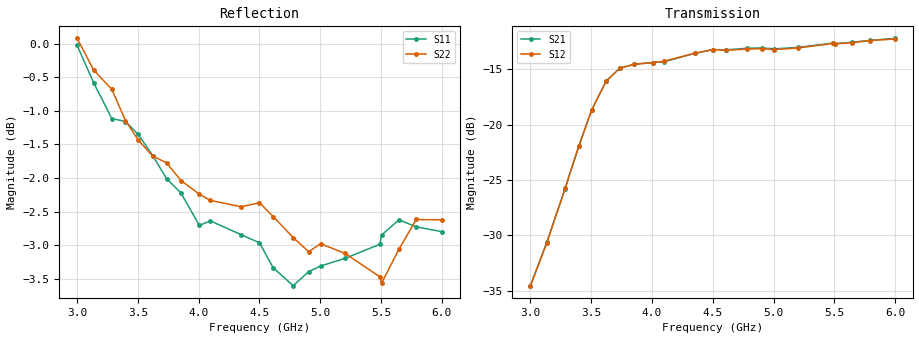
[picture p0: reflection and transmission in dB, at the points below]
!  26/11/2025  13:56:33
! Ref Plane: 0.000 mm
# MHZ S MA R  50
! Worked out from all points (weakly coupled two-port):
!   401 points, 3 GHz to 6 GHz, reference 50 ohm
!   highest |S21| = -12.19 dB at 6 GHz (marker M1); lowest = -34.5 dB at 3 GHz (marker M2)
!   lowest |S11| = -3.6 dB at 4.777 GHz (marker M3), VSWR 4.89, Z = 119 - j117 ohm
!   |S11| at or under -10 dB: nowhere
!   |S22| runs from -3.6 to 0.2 dB; largest |S21 - S12| = 0.01
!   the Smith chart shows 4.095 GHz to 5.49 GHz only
!   S11 on the Smith chart (normalised r, x): 4.095 GHz: 0.15, -0.11; 4.35 GHz: 0.24, +0.68; 4.612 GHz: 2.36, +2.51; 4.905 GHz: 0.62, -1.40; 5.205 GHz: 0.19, -0.22; 5.49 GHz: 0.22, +0.53
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3000  0.9968 -139.1  0.01875 56.7  0.01877 58.5  1.009 -105.2
3135  0.9353 -170.7  0.02954 22.5  0.02927 24.5  0.9559 -137.2
3285  0.8795 146.8  0.05152 -19.4  0.0516 -17.7  0.9246 -174.6
3397.5  0.8751 108.0  0.08004 -57.7  0.08024 -56.4  0.8764 149.8
3502.5  0.8559 65.3  0.1163 -99.5  0.1162 -98.1  0.8478 112.0
3622.5  0.8251 15.0  0.1577 -151.4  0.1575 -150.1  0.8246 60.5
3735  0.7936 -33.5  0.1802 159.6  0.1801 161.1  0.8153 11.2
3855  0.7741 -81.3  0.1878 111.5  0.1878 113.1  0.7908 -37.8
4005  0.7324 -135.6  0.1912 58.4  0.1909 59.6  0.7727 -90.4
4095  0.7382 -166.9  0.1923 28.2  0.1936 29.7  0.7645 -120.5
4350  0.7208 109.3  0.2102 -52.7  0.2105 -50.8  0.7562 163.1
4500  0.711 61.0  0.2186 -100.7  0.2186 -99.2  0.7614 117.6
4612.5  0.6812 24.8  0.2183 -135.8  0.2169 -134.8  0.7437 81.6
4777.5  0.6606 -24.8  0.2215 174.4  0.2199 176.0  0.7173 32.7
4905  0.6768 -64.5  0.2228 137.5  0.2209 139.2  0.7002 -2.8
5002.5  0.6831 -94.7  0.2203 109.5  0.2185 110.8  0.7098 -32.2
5205  0.6924 -153.9  0.2239 52.0  0.2226 53.2  0.6981 -89.6
5490  0.7091 122.8  0.2342 -29.0  0.2331 -26.8  0.6707 -168.1
5505  0.7205 118.8  0.2327 -33.3  0.2321 -31.1  0.6636 -176.1
5647.5  0.7395 79.5  0.2361 -73.3  0.2348 -71.0  0.7032 143.3
5790  0.7306 40.0  0.2406 -113.9  0.2402 -111.6  0.7399 104.5
6000  0.7247 -20.6  0.2458 -173.3  0.2442 -171.7  0.7394 52.4
